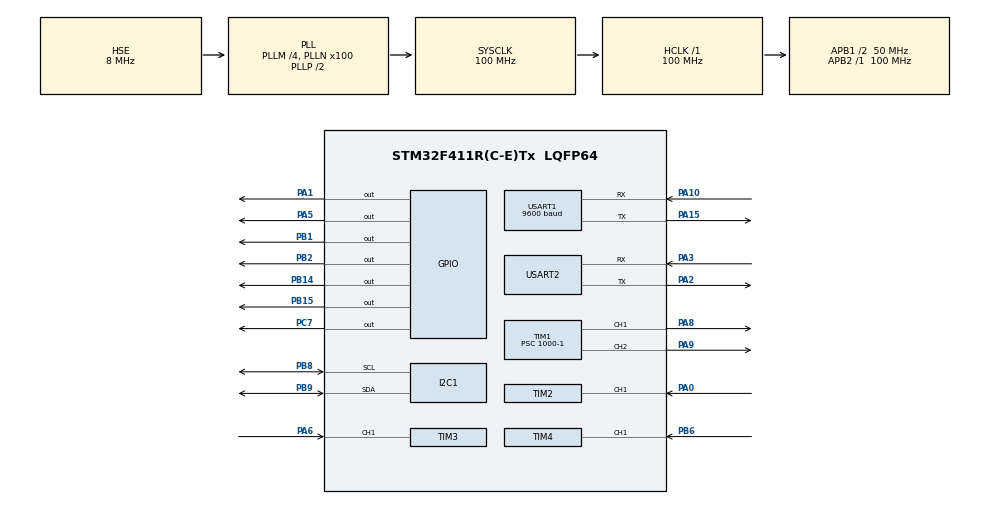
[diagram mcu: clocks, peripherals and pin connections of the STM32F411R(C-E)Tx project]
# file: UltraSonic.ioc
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Mcu.Family=STM32F4
Mcu.Name=STM32F411R(C-E)Tx
Mcu.Package=LQFP64
NVIC.PriorityGroup=NVIC_PRIORITYGROUP_4
NVIC.TIM2_IRQn=true\:0\:0\:false\:false\:true\:true\:true\:true
NVIC.TIM3_IRQn=true\:0\:0\:false\:false\:true\:true\:true\:true
NVIC.TIM4_IRQn=true\:0\:0\:false\:false\:true\:true\:true\:true
NVIC.USART1_IRQn=true\:0\:0\:false\:false\:true\:true\:true\:true
NVIC.USART2_IRQn=true\:0\:0\:false\:false\:true\:true\:true\:true
PA0-WKUP.Signal=S_TIM2_CH1_ETR
PA1.Signal=GPIO_Output
PA10.Mode=Asynchronous
PA10.Signal=USART1_RX
PA13.Mode=Serial_Wire
PA13.Signal=SYS_JTMS-SWDIO
PA14.Mode=Serial_Wire
PA14.Signal=SYS_JTCK-SWCLK
PA15.Mode=Asynchronous
PA15.Signal=USART1_TX
PA2.Mode=Asynchronous
PA2.Signal=USART2_TX
PA3.Mode=Asynchronous
PA3.Signal=USART2_RX
PA5.GPIO_Speed=GPIO_SPEED_FREQ_HIGH
PA5.Signal=GPIO_Output
PA6.Signal=S_TIM3_CH1
PA8.Signal=S_TIM1_CH1
PA9.Signal=S_TIM1_CH2
PB1.Signal=GPIO_Output
PB14.Signal=GPIO_Output
PB15.Signal=GPIO_Output
PB2.Signal=GPIO_Output
PB6.Signal=S_TIM4_CH1
PB8.Mode=I2C
PB8.Signal=I2C1_SCL
PB9.Mode=I2C
PB9.Signal=I2C1_SDA
PC7.Signal=GPIO_Output
PH0\ -\ OSC_IN.Mode=HSE-External-Oscillator
PH0\ -\ OSC_IN.Signal=RCC_OSC_IN
PH1\ -\ OSC_OUT.Mode=HSE-External-Oscillator
PH1\ -\ OSC_OUT.Signal=RCC_OSC_OUT
ProjectManager.HeapSize=0x200
ProjectManager.StackSize=0x400
ProjectManager.TargetToolchain=STM32CubeIDE
RCC.48MHZClocksFreq_Value=50000000
RCC.AHBFreq_Value=100000000
RCC.APB1CLKDivider=RCC_HCLK_DIV2
RCC.APB1Freq_Value=50000000
RCC.APB1TimFreq_Value=100000000
RCC.APB2Freq_Value=100000000
RCC.APB2TimFreq_Value=100000000
RCC.CortexFreq_Value=100000000
RCC.HCLKFreq_Value=100000000
RCC.HSE_VALUE=8000000
RCC.HSI_VALUE=16000000
RCC.LSE_VALUE=32768
RCC.PLLM=4
RCC.PLLN=100
RCC.PLLSourceVirtual=RCC_PLLSOURCE_HSE
RCC.SYSCLKFreq_VALUE=100000000
RCC.SYSCLKSource=RCC_SYSCLKSOURCE_PLLCLK
RCC.VCOOutputFreq_Value=200000000
SH.S_TIM1_CH1.0=TIM1_CH1,PWM Generation1 CH1
SH.S_TIM1_CH2.0=TIM1_CH2,PWM Generation2 CH2
SH.S_TIM2_CH1_ETR.0=TIM2_CH1,Input_Capture1_from_TI1
SH.S_TIM3_CH1.0=TIM3_CH1,Input_Capture1_from_TI1
SH.S_TIM4_CH1.0=TIM4_CH1,Input_Capture1_from_TI1
TIM1.Channel-PWM\ Generation1\ CH1=TIM_CHANNEL_1
TIM1.Channel-PWM\ Generation2\ CH2=TIM_CHANNEL_2
TIM1.Period=1000-1
TIM1.Prescaler=1000-1
TIM2.Channel-Input_Capture1_from_TI1=TIM_CHANNEL_1
TIM2.ICFilter_CH1=0
TIM2.Period=65535-1
TIM2.Prescaler=100-1
TIM3.Channel-Input_Capture1_from_TI1=TIM_CHANNEL_1
TIM3.ICFilter_CH1=0
TIM3.Period=65535-1
TIM3.Prescaler=100-1
TIM4.Channel-Input_Capture1_from_TI1=TIM_CHANNEL_1
TIM4.ICFilter_CH1=0
TIM4.Period=65535-1
TIM4.Prescaler=100-1
USART1.BaudRate=9600
USART1.VirtualMode=VM_ASYNC
USART2.VirtualMode=VM_ASYNC
VP_TIM1_VS_ClockSourceINT.Mode=Internal
VP_TIM2_VS_ClockSourceINT.Mode=Internal
VP_TIM3_VS_ClockSourceINT.Mode=Internal
VP_TIM4_VS_ClockSourceINT.Mode=Internal
board=custom

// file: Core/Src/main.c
/* USER CODE BEGIN Header */
/**
  ******************************************************************************
  * @file           : main.c
  * @brief          : Main program body
  ******************************************************************************
  * @attention
  *
  * Copyright (c) 2024 STMicroelectronics.
  * All rights reserved.
  *
  * This software is licensed under terms that can be found in the LICENSE file
  * in the root directory of this software component.
  * If no LICENSE file comes with this software, it is provided AS-IS.
  *
  ******************************************************************************
  */
/* USER CODE END Header */
#include "main.h"
#include "cmsis_os.h"

/* USER CODE BEGIN Includes */
#include "stdio.h"
#include <string.h>
/* USER CODE END Includes */

/* USER CODE BEGIN PD */
#define TRIG_PORT1 GPIOC
#define TRIG_PIN1 GPIO_PIN_7

#define TRIG_PORT2 GPIOA
#define TRIG_PIN2 GPIO_PIN_1

#define TRIG_PORT3 GPIOA
#define TRIG_PIN3 GPIO_PIN_5

#define I2C_ADDR 0x27 // I2C address of the PCF8574
#define RS_BIT 0 // Register select bit
#define EN_BIT 2 // Enable bit
#define BL_BIT 3 // Backlight bit
#define D4_BIT 4 // Data 4 bit
#define D5_BIT 5 // Data 5 bit
#define D6_BIT 6 // Data 6 bit
#define D7_BIT 7 // Data 7 bit

#define LCD_ROWS 2 // Number of rows on the LCD
#define LCD_COLS 16 // Number of columns on the LCD
/* USER CODE END PD */

I2C_HandleTypeDef hi2c1;

TIM_HandleTypeDef htim1;
TIM_HandleTypeDef htim2;
TIM_HandleTypeDef htim3;
TIM_HandleTypeDef htim4;

UART_HandleTypeDef huart1;
UART_HandleTypeDef huart2;

osThreadId SonicTaskHandle;
osThreadId MotorTaskHandle;
osThreadId LedTaskHandle;
/* USER CODE BEGIN PV */
uint32_t INC_Value11=0;      // first capture
uint32_t INC_Value12=0;      // 2nd capture
uint32_t echoTime1=0;        // between Rising, Falling
uint8_t captureFlag1=0;
uint8_t distance1=0;         // distance

uint32_t INC_Value21=0;      // first capture
uint32_t INC_Value22=0;      // 2nd capture
uint32_t echoTime2=0;        // between Rising, Falling
uint8_t captureFlag2=0;
uint8_t distance2=0;         // distance

uint32_t INC_Value31=0;      // first capture
uint32_t INC_Value32=0;      // 2nd capture
uint32_t echoTime3=0;        // between Rising, Falling
uint8_t captureFlag3=0;
uint8_t distance3=0;         // distance
uint8_t backlight_state = 1;
uint8_t bt_data[1];
int m = 1;
/* USER CODE END PV */

void SystemClock_Config(void);
static void MX_GPIO_Init(void);
static void MX_TIM3_Init(void);
static void MX_USART2_UART_Init(void);
static void MX_TIM2_Init(void);
static void MX_TIM4_Init(void);
static void MX_TIM1_Init(void);
static void MX_USART1_UART_Init(void);
static void MX_I2C1_Init(void);
void StartDefaultTask(void const * argument);
void StartTask02(void const * argument);
void StartTask03(void const * argument);

/* USER CODE BEGIN PFP */

void HAL_UART_RxCpltCallback(UART_HandleTypeDef *huart)
{
	if(huart->Instance==USART1)
	{

		HAL_UART_Receive_IT(&huart1, bt_data, sizeof(bt_data));
	}
}

void delay_us(uint16_t us){
  __HAL_TIM_SET_COUNTER(&htim3,0);
  while((__HAL_TIM_GET_COUNTER(&htim3))<us);
}

void HAL_TIM_IC_CaptureCallback(TIM_HandleTypeDef *htim)
{
    if(htim == &htim4)
    {
        if(captureFlag1== 0) //first value not capture
        {
            INC_Value11 = HAL_TIM_ReadCapturedValue(&htim4,TIM_CHANNEL_1); //read the first value
            captureFlag1 = 1;

            __HAL_TIM_SET_CAPTUREPOLARITY(htim,TIM_CHANNEL_1,TIM_INPUTCHANNELPOLARITY_FALLING);
        }
        else if(captureFlag1==1) //first is already value
        {
            INC_Value12= HAL_TIM_ReadCapturedValue(&htim4, TIM_CHANNEL_1);
            __HAL_TIM_SET_COUNTER(htim,0);
            if(INC_Value12 >INC_Value11)// normal
            {
                echoTime1 = INC_Value12-INC_Value11;
            }
            else if(INC_Value11 > INC_Value12)
            {
                echoTime1 = (0xffff-INC_Value11)+ INC_Value12;
            }
            distance1 = echoTime1 / 58;
            captureFlag1 = 0;

            __HAL_TIM_SET_CAPTUREPOLARITY(htim,TIM_CHANNEL_1,TIM_INPUTCHANNELPOLARITY_RISING);
            __HAL_TIM_DISABLE_IT(&htim4, TIM_IT_CC1);
        }
    }

    if(htim == &htim2)
    {
        if(captureFlag2== 0) //first value not capture
        {
            INC_Value21 = HAL_TIM_ReadCapturedValue(&htim2,TIM_CHANNEL_1); //read the first value
            captureFlag2 = 1;

            __HAL_TIM_SET_CAPTUREPOLARITY(htim,TIM_CHANNEL_1,TIM_INPUTCHANNELPOLARITY_FALLING);
        }
        else if(captureFlag2==1) //first is already value
        {
            INC_Value22= HAL_TIM_ReadCapturedValue(&htim2, TIM_CHANNEL_1);
            __HAL_TIM_SET_COUNTER(htim,0);
            if(INC_Value22 >INC_Value21)// normal
            {
                echoTime2 = INC_Value22-INC_Value21;
            }
            else if(INC_Value21 > INC_Value22)
            {
                echoTime2= (0xffff-INC_Value21)+ INC_Value22;
            }
            distance2 = echoTime2 / 58;
            captureFlag2 = 0;

            __HAL_TIM_SET_CAPTUREPOLARITY(htim,TIM_CHANNEL_1,TIM_INPUTCHANNELPOLARITY_RISING);
            __HAL_TIM_DISABLE_IT(&htim2, TIM_IT_CC1);
        }
    }

    if(htim == &htim3)
    {
        if(captureFlag3== 0) //first value not capture
        {
            INC_Value31 = HAL_TIM_ReadCapturedValue(&htim3,TIM_CHANNEL_1); //read the first value
            captureFlag3 = 1;

            __HAL_TIM_SET_CAPTUREPOLARITY(htim,TIM_CHANNEL_1,TIM_INPUTCHANNELPOLARITY_FALLING);
        }
        else if(captureFlag3==1) //first is already value
        {
            INC_Value32= HAL_TIM_ReadCapturedValue(&htim3, TIM_CHANNEL_1);
            __HAL_TIM_SET_COUNTER(htim,0);
            if(INC_Value32 >INC_Value31)// normal
            {
                echoTime3 = INC_Value32-INC_Value31;
            }
            else if(INC_Value31 > INC_Value32)
            {
                echoTime3 = (0xffff-INC_Value31)+ INC_Value32;
            }
            distance3 = echoTime3 / 58;
            captureFlag3 = 0;

            __HAL_TIM_SET_CAPTUREPOLARITY(htim,TIM_CHANNEL_1,TIM_INPUTCHANNELPOLARITY_RISING);
            __HAL_TIM_DISABLE_IT(&htim3, TIM_IT_CC1);
        }
    }
}

// ===================================LCD================================

void lcd_write_nibble(uint8_t nibble, uint8_t rs) {
  uint8_t data = nibble << D4_BIT;
  data |= rs << RS_BIT;
  data |= backlight_state << BL_BIT; // Include backlight state in data
  data |= 1 << EN_BIT;
  HAL_I2C_Master_Transmit(&hi2c1, I2C_ADDR << 1, &data, 1, 100);
  HAL_Delay(1);
  data &= ~(1 << EN_BIT);
  HAL_I2C_Master_Transmit(&hi2c1, I2C_ADDR << 1, &data, 1, 100);
}
void lcd_send_cmd(uint8_t cmd) {
  uint8_t upper_nibble = cmd >> 4;
  uint8_t lower_nibble = cmd & 0x0F;
  lcd_write_nibble(upper_nibble, 0);
  lcd_write_nibble(lower_nibble, 0);
  if (cmd == 0x01 || cmd == 0x02) {
    HAL_Delay(2);
  }
}

void lcd_send_data(uint8_t data) {
  uint8_t upper_nibble = data >> 4;
  uint8_t lower_nibble = data & 0x0F;
  lcd_write_nibble(upper_nibble, 1);
  lcd_write_nibble(lower_nibble, 1);
}

void lcd_init() {
  HAL_Delay(50);
  lcd_write_nibble(0x03, 0);
  HAL_Delay(5);
  lcd_write_nibble(0x03, 0);
  HAL_Delay(1);
  lcd_write_nibble(0x03, 0);
  HAL_Delay(1);
  lcd_write_nibble(0x02, 0);
  lcd_send_cmd(0x28);
  lcd_send_cmd(0x0C);
  lcd_send_cmd(0x06);
  lcd_send_cmd(0x01);
  HAL_Delay(2);
}

void lcd_write_string(char *str) {
  while (*str) {
    lcd_send_data(*str++);
  }
}

void lcd_set_cursor(uint8_t row, uint8_t column) {
    uint8_t address;
    switch (row) {
        case 0:
            address = 0x00;
            break;
        case 1:
            address = 0x40;
            break;
        default:
            address = 0x00;
    }
    address += column;
    lcd_send_cmd(0x80 | address);
}

void lcd_clear(void) {
	lcd_send_cmd(0x01);
    HAL_Delay(2);
}

void lcd_backlight(uint8_t state) {
  if (state) {
    backlight_state = 1;
  } else {
    backlight_state = 0;
  }
}

//================== Ultra Sonic===================================

void sonic1(void) // Trig pin 10us
{
    HAL_GPIO_WritePin(TRIG_PORT1, TRIG_PIN1, GPIO_PIN_SET);
    delay_us(10);
    HAL_GPIO_WritePin(TRIG_PORT1, TRIG_PIN1, GPIO_PIN_RESET);

    __HAL_TIM_ENABLE_IT(&htim4,TIM_IT_CC1);
}

void sonic2(void) // Trig pin 10us
{
    HAL_GPIO_WritePin(TRIG_PORT2, TRIG_PIN2, GPIO_PIN_SET);
    delay_us(10);
    HAL_GPIO_WritePin(TRIG_PORT2, TRIG_PIN2, GPIO_PIN_RESET);

    __HAL_TIM_ENABLE_IT(&htim2,TIM_IT_CC1);
}

void sonic3(void) // Trig pin 10us
{
    HAL_GPIO_WritePin(TRIG_PORT3, TRIG_PIN3, GPIO_PIN_SET);
    delay_us(10);
    HAL_GPIO_WritePin(TRIG_PORT3, TRIG_PIN3, GPIO_PIN_RESET);

    __HAL_TIM_ENABLE_IT(&htim3,TIM_IT_CC1);
}

void go()
{
    HAL_GPIO_WritePin(GPIOB, GPIO_PIN_4, 0);		// go	//in1
    HAL_GPIO_WritePin(GPIOB, GPIO_PIN_5, 1);				//in2
    HAL_GPIO_WritePin(GPIOB, GPIO_PIN_3, 1);				//in3
    HAL_GPIO_WritePin(GPIOA, GPIO_PIN_10, 0);				//in4

}

void back()
{
    HAL_GPIO_WritePin(GPIOB, GPIO_PIN_4, 1);		// go
    HAL_GPIO_WritePin(GPIOB, GPIO_PIN_5, 0);
    HAL_GPIO_WritePin(GPIOB, GPIO_PIN_3, 0);
    HAL_GPIO_WritePin(GPIOA, GPIO_PIN_10, 1);

}

void left()
{
    HAL_GPIO_WritePin(GPIOB, GPIO_PIN_4, 1);
    HAL_GPIO_WritePin(GPIOB, GPIO_PIN_5, 0);
    HAL_GPIO_WritePin(GPIOB, GPIO_PIN_3, 1);
    HAL_GPIO_WritePin(GPIOA, GPIO_PIN_10, 0);
}

void right()
{
    HAL_GPIO_WritePin(GPIOB, GPIO_PIN_4, 0);
    HAL_GPIO_WritePin(GPIOB, GPIO_PIN_5, 1);
    HAL_GPIO_WritePin(GPIOB, GPIO_PIN_3, 0);
    HAL_GPIO_WritePin(GPIOA, GPIO_PIN_10, 1);

}

void stop()
{
    HAL_GPIO_WritePin(GPIOB, GPIO_PIN_4, 1);
    HAL_GPIO_WritePin(GPIOB, GPIO_PIN_5, 1);
    HAL_GPIO_WritePin(GPIOB, GPIO_PIN_3, 1);
    HAL_GPIO_WritePin(GPIOA, GPIO_PIN_10, 1);

}
/* USER CODE END PFP */

int main(void)
{

  /* MCU Configuration--------------------------------------------------------*/

  /* Reset of all peripherals, Initializes the Flash interface and the Systick. */
  HAL_Init();

  /* Configure the system clock */
  SystemClock_Config();

  /* Initialize all configured peripherals */
  MX_GPIO_Init();
  MX_TIM3_Init();
  MX_USART2_UART_Init();
  MX_TIM2_Init();
  MX_TIM4_Init();
  MX_TIM1_Init();
  MX_USART1_UART_Init();
  MX_I2C1_Init();
  /* USER CODE BEGIN 2 */
  HAL_TIM_IC_Start_IT(&htim4, TIM_CHANNEL_1);
  HAL_TIM_IC_Start_IT(&htim2, TIM_CHANNEL_1);
  HAL_TIM_IC_Start_IT(&htim3, TIM_CHANNEL_1);
  HAL_TIM_PWM_Start(&htim1, TIM_CHANNEL_1);
  HAL_TIM_PWM_Start(&htim1, TIM_CHANNEL_2);

  HAL_UART_Receive_IT(&huart1, bt_data, sizeof(bt_data));

  lcd_backlight(1); // Turn on backlight
  lcd_init();

  /* USER CODE END 2 */

  /* Create the thread(s) */
  /* definition and creation of SonicTask */
  osThreadDef(SonicTask, StartDefaultTask, osPriorityNormal, 0, 128);
  SonicTaskHandle = osThreadCreate(osThread(SonicTask), NULL);

  /* definition and creation of MotorTask */
  osThreadDef(MotorTask, StartTask02, osPriorityIdle, 0, 128);
  MotorTaskHandle = osThreadCreate(osThread(MotorTask), NULL);

  /* definition and creation of LedTask */
  osThreadDef(LedTask, StartTask03, osPriorityIdle, 0, 128);
  LedTaskHandle = osThreadCreate(osThread(LedTask), NULL);

  /* Start scheduler */
  osKernelStart();
  /* We should never get here as control is now taken by the scheduler */
  /* Infinite loop */
  while (1)
  {

  }
}

void SystemClock_Config(void)
{
  RCC_OscInitTypeDef RCC_OscInitStruct = {0};
  RCC_ClkInitTypeDef RCC_ClkInitStruct = {0};

  /** Configure the main internal regulator output voltage
  */
  __HAL_RCC_PWR_CLK_ENABLE();
  __HAL_PWR_VOLTAGESCALING_CONFIG(PWR_REGULATOR_VOLTAGE_SCALE1);

  /** Initializes the RCC Oscillators according to the specified parameters
  * in the RCC_OscInitTypeDef structure.
  */
  RCC_OscInitStruct.OscillatorType = RCC_OSCILLATORTYPE_HSE;
  RCC_OscInitStruct.HSEState = RCC_HSE_ON;
  RCC_OscInitStruct.PLL.PLLState = RCC_PLL_ON;
  RCC_OscInitStruct.PLL.PLLSource = RCC_PLLSOURCE_HSE;
  RCC_OscInitStruct.PLL.PLLM = 4;
  RCC_OscInitStruct.PLL.PLLN = 100;
  RCC_OscInitStruct.PLL.PLLP = RCC_PLLP_DIV2;
  RCC_OscInitStruct.PLL.PLLQ = 4;
  if (HAL_RCC_OscConfig(&RCC_OscInitStruct) != HAL_OK)
  {
    Error_Handler();v

  }

  /** Initializes the CPU, AHB and APB buses clocks
  */
  RCC_ClkInitStruct.ClockType = RCC_CLOCKTYPE_HCLK|RCC_CLOCKTYPE_SYSCLK
                              |RCC_CLOCKTYPE_PCLK1|RCC_CLOCKTYPE_PCLK2;
  RCC_ClkInitStruct.SYSCLKSource = RCC_SYSCLKSOURCE_PLLCLK;
  RCC_ClkInitStruct.AHBCLKDivider = RCC_SYSCLK_DIV1;
  RCC_ClkInitStruct.APB1CLKDivider = RCC_HCLK_DIV2;
  RCC_ClkInitStruct.APB2CLKDivider = RCC_HCLK_DIV1;

  if (HAL_RCC_ClockConfig(&RCC_ClkInitStruct, FLASH_LATENCY_3) != HAL_OK)
  {
    Error_Handler();
  }
}

static void MX_I2C1_Init(void)
{

  hi2c1.Instance = I2C1;
  hi2c1.Init.ClockSpeed = 100000;
  hi2c1.Init.DutyCycle = I2C_DUTYCYCLE_2;
  hi2c1.Init.OwnAddress1 = 0;
  hi2c1.Init.AddressingMode = I2C_ADDRESSINGMODE_7BIT;
  hi2c1.Init.DualAddressMode = I2C_DUALADDRESS_DISABLE;
  hi2c1.Init.OwnAddress2 = 0;
  hi2c1.Init.GeneralCallMode = I2C_GENERALCALL_DISABLE;
  hi2c1.Init.NoStretchMode = I2C_NOSTRETCH_DISABLE;
  if (HAL_I2C_Init(&hi2c1) != HAL_OK)
  {
    Error_Handler();
  }

}

static void MX_TIM1_Init(void)
{

  TIM_ClockConfigTypeDef sClockSourceConfig = {0};
  TIM_MasterConfigTypeDef sMasterConfig = {0};
  TIM_OC_InitTypeDef sConfigOC = {0};
  TIM_BreakDeadTimeConfigTypeDef sBreakDeadTimeConfig = {0};

  htim1.Instance = TIM1;
  htim1.Init.Prescaler = 1000-1;
  htim1.Init.CounterMode = TIM_COUNTERMODE_UP;
  htim1.Init.Period = 1000-1;
  htim1.Init.ClockDivision = TIM_CLOCKDIVISION_DIV1;
  htim1.Init.RepetitionCounter = 0;
  htim1.Init.AutoReloadPreload = TIM_AUTORELOAD_PRELOAD_DISABLE;
  if (HAL_TIM_Base_Init(&htim1) != HAL_OK)
  {
    Error_Handler();
  }
  sClockSourceConfig.ClockSource = TIM_CLOCKSOURCE_INTERNAL;
  if (HAL_TIM_ConfigClockSource(&htim1, &sClockSourceConfig) != HAL_OK)
  {
    Error_Handler();
  }
  if (HAL_TIM_PWM_Init(&htim1) != HAL_OK)
  {
    Error_Handler();
  }
  sMasterConfig.MasterOutputTrigger = TIM_TRGO_RESET;
  sMasterConfig.MasterSlaveMode = TIM_MASTERSLAVEMODE_DISABLE;
  if (HAL_TIMEx_MasterConfigSynchronization(&htim1, &sMasterConfig) != HAL_OK)
  {
    Error_Handler();
  }
  sConfigOC.OCMode = TIM_OCMODE_PWM1;
  sConfigOC.Pulse = 0;
  sConfigOC.OCPolarity = TIM_OCPOLARITY_HIGH;
  sConfigOC.OCNPolarity = TIM_OCNPOLARITY_HIGH;
  sConfigOC.OCFastMode = TIM_OCFAST_DISABLE;
  sConfigOC.OCIdleState = TIM_OCIDLESTATE_RESET;
  sConfigOC.OCNIdleState = TIM_OCNIDLESTATE_RESET;
  if (HAL_TIM_PWM_ConfigChannel(&htim1, &sConfigOC, TIM_CHANNEL_1) != HAL_OK)
  {
    Error_Handler();
  }
  if (HAL_TIM_PWM_ConfigChannel(&htim1, &sConfigOC, TIM_CHANNEL_2) != HAL_OK)
  {
    Error_Handler();
  }
  sBreakDeadTimeConfig.OffStateRunMode = TIM_OSSR_DISABLE;
  sBreakDeadTimeConfig.OffStateIDLEMode = TIM_OSSI_DISABLE;
  sBreakDeadTimeConfig.LockLevel = TIM_LOCKLEVEL_OFF;
  sBreakDeadTimeConfig.DeadTime = 0;
  sBreakDeadTimeConfig.BreakState = TIM_BREAK_DISABLE;
  sBreakDeadTimeConfig.BreakPolarity = TIM_BREAKPOLARITY_HIGH;
  sBreakDeadTimeConfig.AutomaticOutput = TIM_AUTOMATICOUTPUT_DISABLE;
  if (HAL_TIMEx_ConfigBreakDeadTime(&htim1, &sBreakDeadTimeConfig) != HAL_OK)
  {
    Error_Handler();
  }
  HAL_TIM_MspPostInit(&htim1);

}

static void MX_TIM2_Init(void)
{

  TIM_ClockConfigTypeDef sClockSourceConfig = {0};
  TIM_MasterConfigTypeDef sMasterConfig = {0};
  TIM_IC_InitTypeDef sConfigIC = {0};

  htim2.Instance = TIM2;
  htim2.Init.Prescaler = 100-1;
  htim2.Init.CounterMode = TIM_COUNTERMODE_UP;
  htim2.Init.Period = 65535;
  htim2.Init.ClockDivision = TIM_CLOCKDIVISION_DIV1;
  htim2.Init.AutoReloadPreload = TIM_AUTORELOAD_PRELOAD_DISABLE;
  if (HAL_TIM_Base_Init(&htim2) != HAL_OK)
  {
    Error_Handler();
  }
  sClockSourceConfig.ClockSource = TIM_CLOCKSOURCE_INTERNAL;
  if (HAL_TIM_ConfigClockSource(&htim2, &sClockSourceConfig) != HAL_OK)
  {
    Error_Handler();
  }
  if (HAL_TIM_IC_Init(&htim2) != HAL_OK)
  {
    Error_Handler();
  }
  sMasterConfig.MasterOutputTrigger = TIM_TRGO_RESET;
  sMasterConfig.MasterSlaveMode = TIM_MASTERSLAVEMODE_DISABLE;
  if (HAL_TIMEx_MasterConfigSynchronization(&htim2, &sMasterConfig) != HAL_OK)
  {
    Error_Handler();
  }
  sConfigIC.ICPolarity = TIM_INPUTCHANNELPOLARITY_RISING;
  sConfigIC.ICSelection = TIM_ICSELECTION_DIRECTTI;
  sConfigIC.ICPrescaler = TIM_ICPSC_DIV1;
  sConfigIC.ICFilter = 5;
  if (HAL_TIM_IC_ConfigChannel(&htim2, &sConfigIC, TIM_CHANNEL_1) != HAL_OK)
  {
    Error_Handler();
  }

}

static void MX_TIM3_Init(void)
{

  TIM_ClockConfigTypeDef sClockSourceConfig = {0};
  TIM_MasterConfigTypeDef sMasterConfig = {0};
  TIM_IC_InitTypeDef sConfigIC = {0};

  htim3.Instance = TIM3;
  htim3.Init.Prescaler = 100-1;
  htim3.Init.CounterMode = TIM_COUNTERMODE_UP;
  htim3.Init.Period = 65535;
  htim3.Init.ClockDivision = TIM_CLOCKDIVISION_DIV1;
  htim3.Init.AutoReloadPreload = TIM_AUTORELOAD_PRELOAD_DISABLE;
  if (HAL_TIM_Base_Init(&htim3) != HAL_OK)
  {
    Error_Handler();
  }
  sClockSourceConfig.ClockSource = TIM_CLOCKSOURCE_INTERNAL;
  if (HAL_TIM_ConfigClockSource(&htim3, &sClockSourceConfig) != HAL_OK)
  {
    Error_Handler();
  }
  if (HAL_TIM_IC_Init(&htim3) != HAL_OK)
  {
    Error_Handler();
  }
  sMasterConfig.MasterOutputTrigger = TIM_TRGO_RESET;
  sMasterConfig.MasterSlaveMode = TIM_MASTERSLAVEMODE_DISABLE;
  if (HAL_TIMEx_MasterConfigSynchronization(&htim3, &sMasterConfig) != HAL_OK)
  {
    Error_Handler();
  }
  sConfigIC.ICPolarity = TIM_INPUTCHANNELPOLARITY_RISING;
  sConfigIC.ICSelection = TIM_ICSELECTION_DIRECTTI;
  sConfigIC.ICPrescaler = TIM_ICPSC_DIV1;
  sConfigIC.ICFilter = 5;
  if (HAL_TIM_IC_ConfigChannel(&htim3, &sConfigIC, TIM_CHANNEL_1) != HAL_OK)
  {
    Error_Handler();
  }

}

static void MX_TIM4_Init(void)
{

  TIM_ClockConfigTypeDef sClockSourceConfig = {0};
  TIM_MasterConfigTypeDef sMasterConfig = {0};
  TIM_IC_InitTypeDef sConfigIC = {0};

  htim4.Instance = TIM4;
  htim4.Init.Prescaler = 100-1;
  htim4.Init.CounterMode = TIM_COUNTERMODE_UP;
  htim4.Init.Period = 65535;
  htim4.Init.ClockDivision = TIM_CLOCKDIVISION_DIV1;
  htim4.Init.AutoReloadPreload = TIM_AUTORELOAD_PRELOAD_DISABLE;
  if (HAL_TIM_Base_Init(&htim4) != HAL_OK)
  {
    Error_Handler();
  }
  sClockSourceConfig.ClockSource = TIM_CLOCKSOURCE_INTERNAL;
  if (HAL_TIM_ConfigClockSource(&htim4, &sClockSourceConfig) != HAL_OK)
  {
    Error_Handler();
  }
  if (HAL_TIM_IC_Init(&htim4) != HAL_OK)
  {
    Error_Handler();
  }
  sMasterConfig.MasterOutputTrigger = TIM_TRGO_RESET;
  sMasterConfig.MasterSlaveMode = TIM_MASTERSLAVEMODE_DISABLE;
  if (HAL_TIMEx_MasterConfigSynchronization(&htim4, &sMasterConfig) != HAL_OK)
  {
    Error_Handler();
  }
  sConfigIC.ICPolarity = TIM_INPUTCHANNELPOLARITY_RISING;
  sConfigIC.ICSelection = TIM_ICSELECTION_DIRECTTI;
  sConfigIC.ICPrescaler = TIM_ICPSC_DIV1;
  sConfigIC.ICFilter = 5;
  if (HAL_TIM_IC_ConfigChannel(&htim4, &sConfigIC, TIM_CHANNEL_1) != HAL_OK)
  {
    Error_Handler();
  }

}

static void MX_USART1_UART_Init(void)
{

  huart1.Instance = USART1;
  huart1.Init.BaudRate = 9600;
  huart1.Init.WordLength = UART_WORDLENGTH_8B;
  huart1.Init.StopBits = UART_STOPBITS_1;
  huart1.Init.Parity = UART_PARITY_NONE;
  huart1.Init.Mode = UART_MODE_TX_RX;
  huart1.Init.HwFlowCtl = UART_HWCONTROL_NONE;
  huart1.Init.OverSampling = UART_OVERSAMPLING_16;
  if (HAL_UART_Init(&huart1) != HAL_OK)
  {
    Error_Handler();
  }

}

static void MX_USART2_UART_Init(void)
{

  huart2.Instance = USART2;
  huart2.Init.BaudRate = 115200;
  huart2.Init.WordLength = UART_WORDLENGTH_8B;
  huart2.Init.StopBits = UART_STOPBITS_1;
  huart2.Init.Parity = UART_PARITY_NONE;
  huart2.Init.Mode = UART_MODE_TX_RX;
  huart2.Init.HwFlowCtl = UART_HWCONTROL_NONE;
  huart2.Init.OverSampling = UART_OVERSAMPLING_16;
  if (HAL_UART_Init(&huart2) != HAL_OK)
  {
    Error_Handler();
  }

}

static void MX_GPIO_Init(void)
{
  GPIO_InitTypeDef GPIO_InitStruct = {0};

  /* GPIO Ports Clock Enable */
  __HAL_RCC_GPIOH_CLK_ENABLE();
  __HAL_RCC_GPIOC_CLK_ENABLE();
  __HAL_RCC_GPIOA_CLK_ENABLE();
  __HAL_RCC_GPIOB_CLK_ENABLE();

  /*Configure GPIO pin Output Level */
  HAL_GPIO_WritePin(GPIOC, GPIO_PIN_0|GPIO_PIN_7, GPIO_PIN_RESET);

  /*Configure GPIO pin Output Level */
  HAL_GPIO_WritePin(GPIOA, GPIO_PIN_1|GPIO_PIN_5|GPIO_PIN_10, GPIO_PIN_RESET);

  /*Configure GPIO pin Output Level */
  HAL_GPIO_WritePin(GPIOB, GPIO_PIN_3|GPIO_PIN_4|GPIO_PIN_5, GPIO_PIN_RESET);

  /*Configure GPIO pins : PC0 PC7 */
  GPIO_InitStruct.Pin = GPIO_PIN_0|GPIO_PIN_7;
  GPIO_InitStruct.Mode = GPIO_MODE_OUTPUT_PP;
  GPIO_InitStruct.Pull = GPIO_NOPULL;
  GPIO_InitStruct.Speed = GPIO_SPEED_FREQ_LOW;
  HAL_GPIO_Init(GPIOC, &GPIO_InitStruct);

  /*Configure GPIO pins : PA1 PA10 */
  GPIO_InitStruct.Pin = GPIO_PIN_1|GPIO_PIN_10;
  GPIO_InitStruct.Mode = GPIO_MODE_OUTPUT_PP;
  GPIO_InitStruct.Pull = GPIO_NOPULL;
  GPIO_InitStruct.Speed = GPIO_SPEED_FREQ_LOW;
  HAL_GPIO_Init(GPIOA, &GPIO_InitStruct);

  /*Configure GPIO pin : PA5 */
  GPIO_InitStruct.Pin = GPIO_PIN_5;
  GPIO_InitStruct.Mode = GPIO_MODE_OUTPUT_PP;
  GPIO_InitStruct.Pull = GPIO_NOPULL;
  GPIO_InitStruct.Speed = GPIO_SPEED_FREQ_HIGH;
  HAL_GPIO_Init(GPIOA, &GPIO_InitStruct);

  /*Configure GPIO pins : PB3 PB4 PB5 */
  GPIO_InitStruct.Pin = GPIO_PIN_3|GPIO_PIN_4|GPIO_PIN_5;
  GPIO_InitStruct.Mode = GPIO_MODE_OUTPUT_PP;
  GPIO_InitStruct.Pull = GPIO_NOPULL;
  GPIO_InitStruct.Speed = GPIO_SPEED_FREQ_LOW;
  HAL_GPIO_Init(GPIOB, &GPIO_InitStruct);

}

void StartDefaultTask(void const * argument)
{
  /* USER CODE BEGIN 5 */
  /* Infinite loop */
	// Ultra sonic
  for(;;)
  {
	sonic1();
	sonic2();
	sonic3();
    osDelay(1);
  }
  /* USER CODE END 5 */
}

void StartTask02(void const * argument)
{
  /* USER CODE BEGIN StartTask02 */
  /* Infinite loop */
	//Motor
  for(;;)
  {
	if(m == 1)
	  {
		stop();

		if(bt_data[0] == 'w')
			{
				TIM1->CCR1 = 1000;
				TIM1->CCR2 = 1000;
				go();
			}
			if(bt_data[0] == 's')
			{
				TIM1->CCR1 = 1000;
				TIM1->CCR2 = 1000;
				back();
			}
			if(bt_data[0] == 'a')
			{
				left();
				TIM1->CCR1 = 1000;
				TIM1->CCR2 = 1000;
			}
			if(bt_data[0] == 'd')
			{
				right();
				TIM1->CCR1 = 1000;
				TIM1->CCR2 = 1000;
			}
			if(bt_data[0] == 'q')
			{
				stop();
			}
	  }
	if(m == 0)
	    {
	    	TIM1->CCR1 = 450;
	    	TIM1->CCR2 = 450;
	    	go();

	    	if(distance2 <= 16 && distance2 >13)
	    	{
	    	    TIM1->CCR1 = 0;
	    	    TIM1->CCR2 = 0;
	    	    if(distance1 > distance3)
	    	    {
	    	        TIM1->CCR1 = 400;
	    	        TIM1->CCR2 = 400;
	    	        left();
	    	    }
	    	    else
	    	    {
					TIM1->CCR1 = 400;
					TIM1->CCR2 = 400;
					right();
				}
			}
			else if(distance1 <= 13)
			{
				TIM1->CCR1 = 400;
				TIM1->CCR2 = 400;
				right();
			}
			else if(distance3 <= 13)
			{
				TIM1->CCR1 = 400;
				TIM1->CCR2 = 400;
				left();
			}
			else if(distance2 <= 10)
			{
				TIM1->CCR1 = 450;
				TIM1->CCR2 = 450;
				back();
				HAL_Delay(20);
				if(distance1 <= 13)
				{
					right();
					TIM1->CCR1 = 400;
					TIM1->CCR2 = 400;
				}
				else if(distance3 <= 13)
				{
					left();
					TIM1->CCR1 = 400;
					TIM1->CCR2 = 400;
				}
			}
	    }

    osDelay(1);
  }
  /* USER CODE END StartTask02 */
}

void StartTask03(void const * argument)
{
  /* USER CODE BEGIN StartTask03 */
  /* Infinite loop */
	//LCD
  char *text = "    PUTT PUTT";
  char int_to_str[10];
  int count = 7777;

  sprintf(int_to_str, "%d", count);
  lcd_clear();
  lcd_set_cursor(0, 0);
  lcd_write_string(text);
  lcd_set_cursor(1, 0);
  lcd_write_string("      7777");
  memset(int_to_str, 0, sizeof(int_to_str));
  for(;;)
  {
	if(bt_data[0] == '1')
	{
		lcd_clear();
		lcd_set_cursor(0, 0);
		lcd_write_string("     CONTROL");
		lcd_set_cursor(1, 0);
		lcd_write_string("      MODE");
		m = 1;		// control mode
	}
	if(bt_data[0] == '0')
	{
		m = 0;		// auto mode
		lcd_clear();
		lcd_set_cursor(0, 0);
		lcd_write_string("   AUTONOMOUS");
		lcd_set_cursor(1, 0);
		lcd_write_string("      MODE");

	}
	if(m == 1)
	{
		stop();

		if(bt_data[0] == 'w')
			{
				lcd_write_string("    GO GO");
			}
			if(bt_data[0] == 's')
			{
				lcd_write_string("     BACK");
			}
			if(bt_data[0] == 'a')
			{
				lcd_write_string("     LEFT");
			}
			if(bt_data[0] == 'd')
			{
				lcd_write_string("    RIGHT");
			}
			if(bt_data[0] == 'q')
			{
				lcd_write_string("       STOP");
			}
	}
    osDelay(1);
  }
  /* USER CODE END StartTask03 */
}

void HAL_TIM_PeriodElapsedCallback(TIM_HandleTypeDef *htim)
{
  if (htim->Instance == TIM5) {
    HAL_IncTick();
  }
}

void Error_Handler(void)
{
  __disable_irq();
  while (1)
  {
  }
}
